VERSION 5.7 ;
  NOWIREEXTENSIONATPIN ON ;
  DIVIDERCHAR "/" ;
  BUSBITCHARS "[]" ;
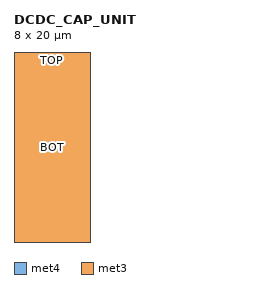
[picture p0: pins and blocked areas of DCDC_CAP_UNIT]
MACRO DCDC_CAP_UNIT
  CLASS BLOCK ;
  FOREIGN DCDC_CAP_UNIT ;
  ORIGIN 0.000 0.000 ;
  SIZE 8.000 BY 20.000 ;
  PIN TOP
    PORT
      LAYER met4 ;
        RECT 0.000 0.000 8.000 20.000 ;
    END
  END TOP
  PIN BOT
    PORT
      LAYER met3 ;
        RECT 0.000 0.000 8.000 20.000 ;
    END
  END BOT
END DCDC_CAP_UNIT
END LIBRARY
